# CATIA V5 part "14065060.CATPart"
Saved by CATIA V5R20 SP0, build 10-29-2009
Part number: 14065060
Definition: NONE
Nomenclature: 14065060
Source: Unknown
Description: 14065060
Bounding box of the stored display mesh (mm): x -30 to 120, y -46.5 to 36.6, z -36.6 to 36.6
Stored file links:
  C:\Users\Utente\Desktop\IO LAVORO\3D X SITO CF\X SITO\PLASTICA\RF2\14065060.CATPart

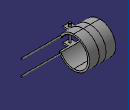
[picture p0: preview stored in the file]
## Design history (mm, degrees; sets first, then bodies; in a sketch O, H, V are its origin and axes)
Body1 "14065060" (main body)
  Solid1: solid without history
